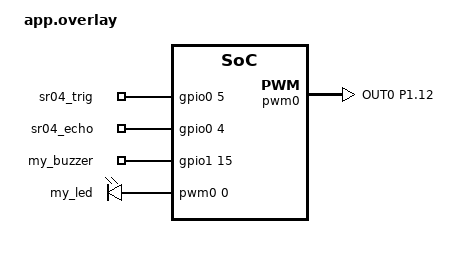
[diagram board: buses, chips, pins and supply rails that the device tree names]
/ {
    aliases {
        sr04-trig = &sr04_trig;
        sr04-echo = &sr04_echo;
        my-buzzer = &my_buzzer;
        my-led = &my_led;
    };

    keypad_pins {
        compatible = "gpio-keys";
        sr04_trig: sr04_trig {
            gpios = <&gpio0 5 (GPIO_ACTIVE_HIGH | GPIO_PULL_UP)>;
        };
        sr04_echo: sr04_echo {
            gpios = <&gpio0 4 (GPIO_ACTIVE_HIGH | GPIO_PULL_UP)>;
        };
        my_buzzer: my_buzzer {
            gpios = <&gpio1 15 (GPIO_ACTIVE_HIGH)>;
        };
    };

    pwm_leds {
        compatible = "pwm-leds";
        my_led: my_led {
            pwms = <&pwm0 0 PWM_MSEC(1) PWM_POLARITY_NORMAL>;
        };
    };
};

&pinctrl {
    pwm0_default: pwm0_default {
        group1 {
            psels = <NRF_PSEL(PWM_OUT0, 1, 12)>;
        };
    };

    pwm0_sleep: pwm0_sleep {
        group1 {
            psels = <NRF_PSEL(PWM_OUT0, 1, 12)>;
            low-power-enable;
        };
    };
};

&pwm0 {
    status = "okay";
    pinctrl-0 = <&pwm0_default>;
    pinctrl-1 = <&pwm0_sleep>;
    pinctrl-names = "default", "sleep";
};
